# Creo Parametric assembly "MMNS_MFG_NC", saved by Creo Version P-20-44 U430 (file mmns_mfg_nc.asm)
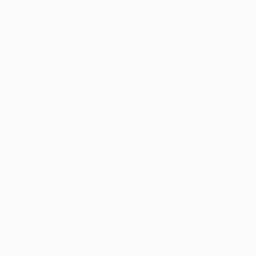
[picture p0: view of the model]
Units: millimeter Newton Second (mmNs); MM, TONNE, SECS

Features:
  1. datum plane "NC_ASM_RIGHT"
  2. datum plane "NC_ASM_TOP"
  3. datum plane "NC_ASM_FRONT"
  4. coordinate system

Other named items: NC_ASM_DEF_CSYS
